VERSION 5.7 ;
  NOWIREEXTENSIONATPIN ON ;
  DIVIDERCHAR "/" ;
  BUSBITCHARS "[]" ;
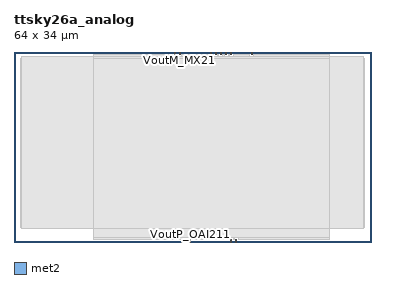
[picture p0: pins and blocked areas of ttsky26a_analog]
MACRO ttsky26a_analog
  CLASS BLOCK ;
  FOREIGN ttsky26a_analog ;
  ORIGIN 0.000 0.000 ;
  SIZE 64.000 BY 34.000 ;
  PIN VoutM_AO22
    ANTENNADIFFAREA 0.340600 ;
    PORT
      LAYER met2 ;
        RECT 37.880 33.515 38.020 34.000 ;
    END
  END VoutM_AO22
  PIN VoutM_MX21
    ANTENNADIFFAREA 0.340600 ;
    PORT
      LAYER met2 ;
        RECT 29.600 33.515 29.740 34.000 ;
    END
  END VoutM_MX21
  PIN VoutM_NAND
    ANTENNADIFFAREA 0.340600 ;
    PORT
      LAYER met2 ;
        RECT 39.720 0.000 39.860 0.485 ;
    END
  END VoutM_NAND
  PIN VoutM_OAI211
    ANTENNADIFFAREA 0.340600 ;
    PORT
      LAYER met2 ;
        RECT 30.520 0.000 30.660 0.485 ;
    END
  END VoutM_OAI211
  PIN VoutP_AO22
    ANTENNADIFFAREA 0.340600 ;
    PORT
      LAYER met2 ;
        RECT 38.800 33.515 38.940 34.000 ;
    END
  END VoutP_AO22
  PIN VoutP_MX21
    ANTENNADIFFAREA 0.340600 ;
    PORT
      LAYER met2 ;
        RECT 28.680 33.515 28.820 34.000 ;
    END
  END VoutP_MX21
  PIN VoutP_NAND
    ANTENNADIFFAREA 0.340600 ;
    PORT
      LAYER met2 ;
        RECT 38.800 0.000 38.940 0.485 ;
    END
  END VoutP_NAND
  PIN VoutP_OAI211
    ANTENNADIFFAREA 0.340600 ;
    PORT
      LAYER met2 ;
        RECT 31.440 0.000 31.580 0.485 ;
    END
  END VoutP_OAI211
  PIN Vout_DIGOTA
    ANTENNADIFFAREA 0.601000 ;
    PORT
      LAYER met2 ;
        RECT 42.480 33.515 42.620 34.000 ;
    END
  END Vout_DIGOTA
  PIN cntrl
    ANTENNAGATEAREA 0.213000 ;
    PORT
      LAYER met2 ;
        RECT 36.960 33.515 37.100 34.000 ;
    END
  END cntrl
  PIN ua[0]
    ANTENNAGATEAREA 1.116000 ;
    PORT
      LAYER met2 ;
        RECT 36.040 33.515 36.180 34.000 ;
    END
  END ua[0]
  PIN ua[1]
    ANTENNAGATEAREA 1.116000 ;
    PORT
      LAYER met2 ;
        RECT 35.120 33.515 35.260 34.000 ;
    END
  END ua[1]
  OBS
      LAYER nwell ;
        RECT 1.190 2.600 62.750 32.830 ;
      LAYER li1 ;
        RECT 1.380 2.635 62.560 32.725 ;
      LAYER met1 ;
        RECT 1.380 2.480 62.560 33.280 ;
      LAYER met2 ;
        RECT 14.180 33.235 28.400 33.515 ;
        RECT 29.100 33.235 29.320 33.515 ;
        RECT 30.020 33.235 34.840 33.515 ;
        RECT 35.540 33.235 35.760 33.515 ;
        RECT 36.460 33.235 36.680 33.515 ;
        RECT 37.380 33.235 37.600 33.515 ;
        RECT 38.300 33.235 38.520 33.515 ;
        RECT 39.220 33.235 42.200 33.515 ;
        RECT 42.900 33.235 56.430 33.515 ;
        RECT 14.180 0.765 56.430 33.235 ;
        RECT 14.180 0.485 30.240 0.765 ;
        RECT 30.940 0.485 31.160 0.765 ;
        RECT 31.860 0.485 38.520 0.765 ;
        RECT 39.220 0.485 39.440 0.765 ;
        RECT 40.140 0.485 56.430 0.765 ;
      LAYER met3 ;
        RECT 14.160 2.555 56.450 32.805 ;
      LAYER met4 ;
        RECT 14.150 2.480 56.460 32.880 ;
  END
END ttsky26a_analog
END LIBRARY

